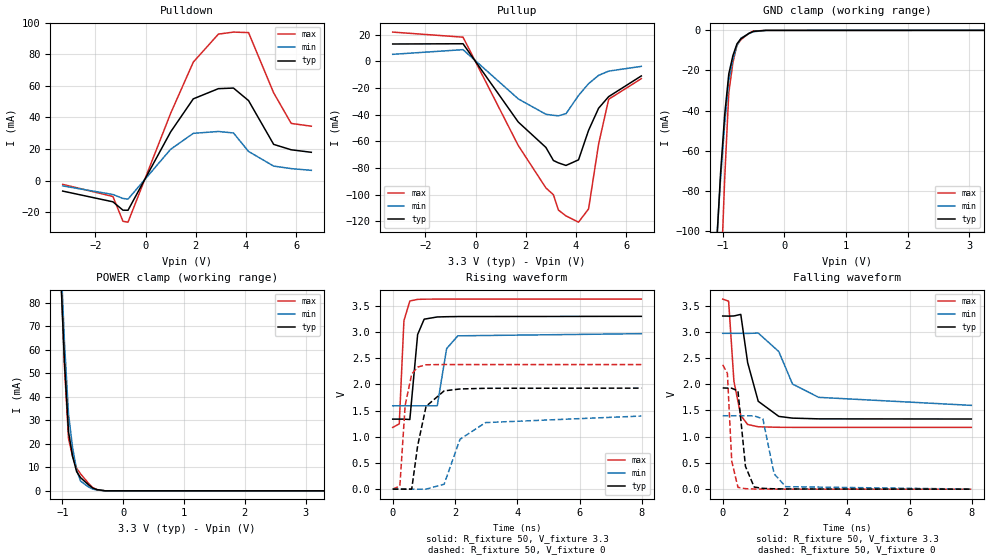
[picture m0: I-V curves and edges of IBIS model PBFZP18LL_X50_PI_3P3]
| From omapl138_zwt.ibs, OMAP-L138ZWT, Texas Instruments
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|   Model Cell PBFZP18LL_X50_PI_3P3
|BC1833DV40CTPBFZ_PI_3P3
[Model]   PBFZP18LL_X50_PI_3P3
Model_type   I/O
Polarity   Non-Inverting
Enable   Active-Low
Vinl =  0.8V
Vinh =  2V
Cref =  15pF
Rref =  100.00M
Vref =  0V
Vmeas =  1.65
C_comp   1.943144p   1.721292p   2.064363p
[Model Spec]
Vinl   0.8V   0.8V   0.8V
Vinh   2V   2V   2V
[Temperature Range]   25   125   -40
[Voltage Range]   3.3   2.97   3.63
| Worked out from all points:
|   slope of the pulldown table from 0 to 0.495 V, typ, clamps not added: 31.5 ohm
|   slope of the pullup table from 0 to 0.495 V, typ, clamps not added: 35.2 ohm
|   GND clamp passes 1 mA (typ) near -0.54 V on its own axis
|   POWER clamp passes 1 mA (typ) near -0.48 V on its own axis
|   rising waveform, R_fixture 50, V_fixture 3.3: 20-80 % time 145ps typ, 209ps min, 99ps max; typ from 1.34 V to 3.3 V
|   rising waveform, R_fixture 50, V_fixture 0: 20-80 % time 317ps typ, 693ps min, 183ps max; typ from 0 V to 1.93 V
|   falling waveform, R_fixture 50, V_fixture 3.3: 20-80 % time 388ps typ, 784ps min, 207ps max; typ from 3.3 V to 1.34 V
|   falling waveform, R_fixture 50, V_fixture 0: 20-80 % time 167ps typ, 250ps min, 117ps max; typ from 1.93 V to 0 V
[POWER_clamp]
|   voltage   I(typ)   I(min)   I(max)
-3.3V     2.432A     2.868A     2.62A
-1.033V   95.07mA    103.2mA    96.84mA
-966.7mV  54.9mA     63.37mA    53mA
-900mV    25.18mA    32.74mA    22.3mA
-833.3mV  14.72mA    18.42mA    14.68mA
-766.7mV  8.18mA     8.87mA     9.635mA
-700mV    5.569mA    4.099mA    7.165mA
-566.7mV  2.472mA    1.574mA    3.06mA
-500mV    1.173mA    752uA      1.317mA
-433.3mV  516.3uA    354.4uA    538.3uA
-300mV    14.19uA    19.01uA    9.9uA
3.3V      -1.3nA     -45.06uA   -185.9pA
[Pulldown]
|   voltage   I(typ)   I(min)   I(max)
-3.3V     -6.708mA   -3.419mA   -2.439mA
-1.3V     -13.52mA   -8.874mA   -10.14mA
-900mV    -18.83mA   -11.38mA   -25.87mA
-700mV    -18.88mA   -11.81mA   -26.45mA
1V        30.91mA    19.84mA    42.7mA
1.9V      51.83mA    29.94mA    75.14mA
2.9V      58.3mA     31.12mA    92.92mA
3.5V      58.67mA    30.17mA    94.2mA
4.1V      50.73mA    18.46mA    93.88mA
5.1V      22.94mA    9.149mA    55.64mA
5.8V      19.5mA     7.56mA     36.23mA
6.6V      17.91mA    6.449mA    34.47mA
[Pullup]
|   voltage   I(typ)   I(min)   I(max)
-3.3V     13.07mA    5.31mA     22.02mA
-500mV    13.27mA    8.819mA    18.2mA
1.7V      -45.56mA   -28.16mA   -63.21mA
2.8V      -64.62mA   -39.71mA   -95.04mA
3.1V      -74.46mA   -40.51mA   -100.2mA
3.3V      -76.24mA   -40.86mA   -111.7mA
3.6V      -78.17mA   -39.29mA   -116.1mA
4.1V      -73.95mA   -25.59mA   -120.8mA
4.5V      -51.77mA   -16.71mA   -110.8mA
4.9V      -35.15mA   -10.47mA   -62.03mA
5.3V      -26.46mA   -7.311mA   -28.43mA
6.6V      -10.91mA   -3.736mA   -12.96mA
[GND_clamp]
|   voltage   I(typ)   I(min)   I(max)
-3.3V     -2.048A    -1.805A    -3.667A
-1.1V     -108.6mA   -106.5mA   -191.4mA
-1.033V   -71.11mA   -74.04mA   -127.7mA
-966.7mV  -42.16mA   -46.82mA   -74.24mA
-900mV    -21.73mA   -24.87mA   -31.1mA
-833.3mV  -12.58mA   -14.46mA   -16.07mA
-766.7mV  -6.686mA   -7.461mA   -7.225mA
-700mV    -4.06mA    -3.87mA    -4.574mA
-566.7mV  -1.399mA   -1.472mA   -1.314mA
-500mV    -498.9uA   -685.1uA   -359.4uA
-300mV    -14.89uA   -26.01uA   -14.51uA
3.233V    1.162uA    14.92uA    3.191uA
[Ramp]
| variable   typ   min   max
dV/dt_f   1.212895/0.3860573n  0.8588519/0.7880321n   1.48543/0.2069936n
dV/dt_r   1.165602/0.3170805n  0.8465119/0.6965622n   1.435237/0.1826464n
R_load = 50
[Rising Waveform]
R_fixture = 50
V_fixture = 3.3
V_fixture_min = 2.97
V_fixture_max = 3.63
|   time   V(typ)   V(min)   V(max)
0s        1.337V     1.591V     1.178V
210ps     1.337V     1.591V     1.247V
360ps     1.337V     1.591V     3.216V
550ps     1.33V      1.591V     3.593V
800ps     2.953V     1.591V     3.624V
1.01ns    3.246V     1.591V     3.628V
1.43ns    3.288V     1.593V     3.629V
1.73ns    3.293V     2.683V     3.63V
2.09ns    3.296V     2.928V     3.63V
7.98ns    3.3V       2.969V     3.63V
[Rising Waveform]
R_fixture = 50
V_fixture = 0
V_fixture_min = 0
V_fixture_max = 0
|   time   V(typ)   V(min)   V(max)
0s        -341.1nV   128nV      -636.8nV
230ps     -95.68nV   446.2nV    61.57mV
400ps     -439.1uV   -138.9nV   1.601V
610ps     714.3uV    -27.73nV   2.196V
800ps     825.8mV    113.5nV    2.331V
1.07ns    1.58V      -27.87uV   2.375V
1.65ns    1.877V     93.73mV    2.38V
2.16ns    1.913V     952.7mV    2.379V
2.98ns    1.926V     1.271V     2.379V
7.98ns    1.929V     1.396V     2.379V
[Falling Waveform]
R_fixture = 50
V_fixture = 3.3
V_fixture_min = 2.97
V_fixture_max = 3.63
|   time   V(typ)   V(min)   V(max)
0s        3.3V       2.97V      3.623V
190ps     3.298V     2.97V      3.582V
360ps     3.301V     2.97V      2.055V
580ps     3.331V     2.97V      1.405V
800ps     2.413V     2.968V     1.233V
1.14ns    1.675V     2.975V     1.189V
1.8ns     1.387V     2.623V     1.179V
2.24ns    1.354V     2.004V     1.178V
3.08ns    1.34V      1.75V      1.178V
7.98ns    1.337V     1.597V     1.178V
[Falling Waveform]
R_fixture = 50
V_fixture = 0
V_fixture_min = 0
V_fixture_max = 0
|   time   V(typ)   V(min)   V(max)
0s        1.929V     1.399V     2.371V
150ps     1.926V     1.399V     2.207V
290ps     1.924V     1.399V     530.8mV
490ps     1.871V     1.399V     33.74mV
730ps     434.9mV    1.398V     9.687mV
1.01ns    40.46mV    1.397V     3.027mV
1.29ns    15.12mV    1.339V     1.132mV
1.65ns    7.037mV    292.8mV    397.4uV
2.02ns    3.708mV    47.33mV    159.9uV
7.98ns    21.02uV    1.137mV    132.1nV
